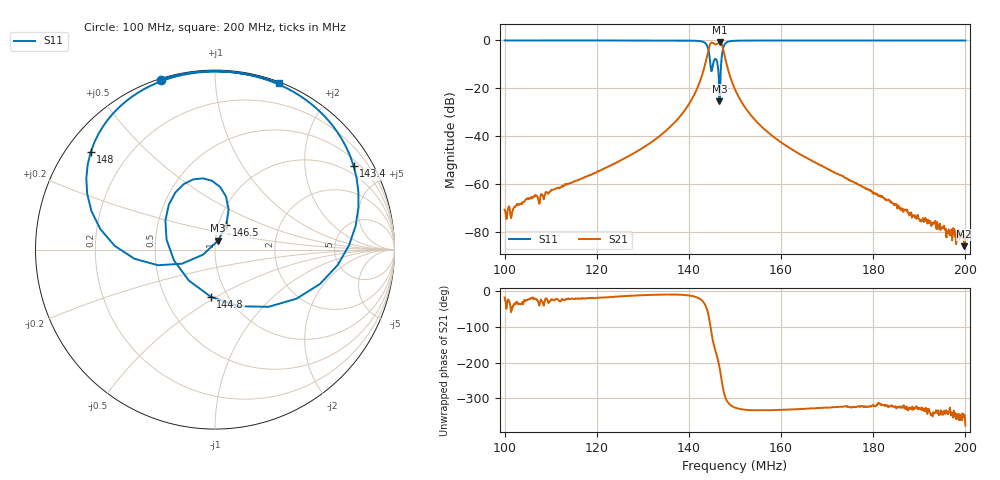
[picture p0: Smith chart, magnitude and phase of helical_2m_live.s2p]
! vnafit live capture, 2-section helical
! device: NanoVNA-H4 over USB CDC
! span 100-200 MHz, 2 segments x 401, 6 averages, IF bw code 1
! S12/S22 not measured by this instrument; written as zero
# Hz S RI R 50
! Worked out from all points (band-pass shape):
!   801 points, 100 MHz to 200 MHz, reference 50 ohm
!   highest |S21| = -0.75 dB at 146.8 MHz (marker M1); lowest = -86.1 dB at 199.8 MHz (marker M2)
!   |S21| within 3 dB of the highest: 144.3 MHz to 147.4 MHz (3.156 MHz wide, 2.16 % of centre)
!   lowest |S11| = -25.6 dB at 146.6 MHz (marker M3), VSWR 1.11, Z = 51.5 + j5.15 ohm
!   |S11| at or under -10 dB: 144.6626 MHz to 145.2402 MHz (577.6 kHz wide, 0.398 % of centre); 146.2 MHz to 147 MHz (778.8 kHz wide, 0.531 % of centre)
!   S12 and S22 are empty: the file has one direction only
!   S11 on the Smith chart (normalised r, x): 100 MHz: 0.00, +0.73; 143.4 MHz: 0.70, +3.47; 144.8 MHz: 0.83, -0.47; 146.5 MHz: 1.09, +0.31; 148 MHz: 0.07, +0.34; 200 MHz: 0.01, +1.45
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1e8  -0.302 0.9469  0.000272 -8.92e-05  0 0  0 0
1.1675e8  -0.1256 0.9865  0.0012 -0.000467  0 0  0 0
1.33375e8  0.1052 0.9873  0.00935 -0.0017  0 0  0 0
1.41e8  0.4222 0.8874  0.0659 -0.0175  0 0  0 0
1.425e8  0.6157 0.7373  0.136 -0.0581  0 0  0 0
1.43375e8  0.7727 0.465  0.2283 -0.1613  0 0  0 0
1.44e8  0.747 0.0237  0.2876 -0.4067  0 0  0 0
1.4475e8  -0.0232 -0.2631  -0.2398 -0.8438  0 0  0 0
1.4525e8  -0.2765 0.161  -0.6925 -0.5365  0 0  0 0
1.4575e8  -0.1217 0.3911  -0.806 -0.1834  0 0  0 0
1.465e8  0.0635 0.1389  -0.8172 0.3634  0 0  0 0
1.46625e8  0.017 0.0499  -0.7697 0.4859  0 0  0 0
1.4675e8  -0.0671 -0.0284  -0.6871 0.6073  0 0  0 0
1.4725e8  -0.5588 0.0208  -0.1025 0.7535  0 0  0 0
1.48e8  -0.6926 0.5423  0.1901 0.3217  0 0  0 0
1.5e8  -0.3679 0.9085  0.0786 0.0527  0 0  0 0
1.56e8  -0.0647 0.9901  0.0133 0.00661  0 0  0 0
1.6675e8  0.104 0.9872  0.00254 0.00158  0 0  0 0
1.83375e8  0.2479 0.961  0.000382 0.000272  0 0  0 0
1.905e8  0.2965 0.947  0.000136 9.41e-05  0 0  0 0
1.9975e8  0.3531 0.9267  4.78e-05 1.24e-05  0 0  0 0
2e8  0.3544 0.9262  6.63e-05 -1.9e-05  0 0  0 0
